VERSION 5.8 ;
BUSBITCHARS "[]" ;
DIVIDERCHAR "/" ;
UNITS DISTANCE MICRONS 2000 ;

# GPIO/Pad Library - tphn7_18gpio_15lm
# 18 metal layers, 15 LM (Local Metal) layers
# Contains I/O pads

# Simple I/O pad
MACRO PAD
  CLASS PAD ;
  ORIGIN 0.0 0.0 ;
  SIZE 10.0 BY 10.0 ;
  SYMMETRY X Y ;
  PIN padin
    DIRECTION INOUT ;
    USE SIGNAL ;
    PORT
      LAYER M5 ;
      RECT 2.0 2.0 3.0 8.0 ;
    END
  END padin
END PAD

# Clock pad
MACRO CLKBUF
  CLASS PAD ;
  ORIGIN 0.0 0.0 ;
  SIZE 10.0 BY 10.0 ;
  SYMMETRY X Y ;
  PIN clk
    DIRECTION INPUT ;
    USE SIGNAL ;
    PORT
      LAYER M5 ;
      RECT 2.0 2.0 3.0 8.0 ;
    END
  END clk
  PIN clkout
    DIRECTION OUTPUT ;
    USE SIGNAL ;
    PORT
      LAYER M5 ;
      RECT 7.0 2.0 8.0 8.0 ;
    END
  END clkout
END CLKBUF

# Layers for pads (higher metal layers)
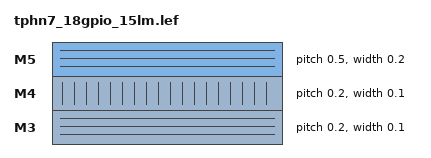
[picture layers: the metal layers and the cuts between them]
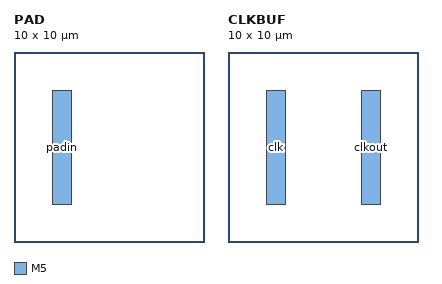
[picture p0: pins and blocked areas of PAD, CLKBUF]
LAYER M3
  TYPE ROUTING ;
  DIRECTION HORIZONTAL ;
  PITCH 0.2 ;
  WIDTH 0.1 ;
END M3

LAYER M4
  TYPE ROUTING ;
  DIRECTION VERTICAL ;
  PITCH 0.2 ;
  WIDTH 0.1 ;
END M4

LAYER M5
  TYPE ROUTING ;
  DIRECTION HORIZONTAL ;
  PITCH 0.5 ;
  WIDTH 0.2 ;
END M5

SITE PAD
  CLASS PAD ;
  SIZE 10.0 BY 10.0 ;
  SYMMETRY X Y ;
END PAD

END LIBRARY
